VERSION 5.7 ;
  NOWIREEXTENSIONATPIN ON ;
  DIVIDERCHAR "/" ;
  BUSBITCHARS "[]" ;
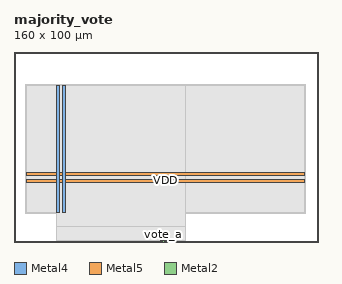
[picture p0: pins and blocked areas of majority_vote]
MACRO majority_vote
  CLASS BLOCK ;
  FOREIGN majority_vote ;
  ORIGIN 0.000 0.000 ;
  SIZE 160.000 BY 100.000 ;
  PIN VDD
    DIRECTION INOUT ;
    USE POWER ;
    PORT
      LAYER Metal4 ;
        RECT 22.240 15.380 23.840 82.620 ;
    END
    PORT
      LAYER Metal5 ;
        RECT 6.720 31.530 152.880 33.130 ;
    END
  END VDD
  PIN VSS
    DIRECTION INOUT ;
    USE GROUND ;
    PORT
      LAYER Metal4 ;
        RECT 25.540 15.380 27.140 82.620 ;
    END
    PORT
      LAYER Metal5 ;
        RECT 6.720 34.830 152.880 36.430 ;
    END
  END VSS
  PIN majority
    DIRECTION OUTPUT ;
    USE SIGNAL ;
    ANTENNADIFFAREA 0.897600 ;
    PORT
      LAYER Metal2 ;
        RECT 79.520 0.000 80.080 0.560 ;
    END
  END majority
  PIN vote_a
    DIRECTION INPUT ;
    USE SIGNAL ;
    ANTENNAGATEAREA 0.396000 ;
    PORT
      LAYER Metal2 ;
        RECT 78.400 0.000 78.960 0.560 ;
    END
  END vote_a
  PIN vote_b
    DIRECTION INPUT ;
    USE SIGNAL ;
    ANTENNAGATEAREA 0.396000 ;
    PORT
      LAYER Metal2 ;
        RECT 80.640 0.000 81.200 0.560 ;
    END
  END vote_b
  PIN vote_c
    DIRECTION INPUT ;
    USE SIGNAL ;
    ANTENNAGATEAREA 0.396000 ;
    PORT
      LAYER Metal2 ;
        RECT 77.280 0.000 77.840 0.560 ;
    END
  END vote_c
  OBS
      LAYER Nwell ;
        RECT 6.290 80.160 153.310 82.750 ;
      LAYER Pwell ;
        RECT 6.290 76.640 153.310 80.160 ;
      LAYER Nwell ;
        RECT 6.290 72.320 153.310 76.640 ;
      LAYER Pwell ;
        RECT 6.290 68.800 153.310 72.320 ;
      LAYER Nwell ;
        RECT 6.290 64.480 153.310 68.800 ;
      LAYER Pwell ;
        RECT 6.290 60.960 153.310 64.480 ;
      LAYER Nwell ;
        RECT 6.290 56.640 153.310 60.960 ;
      LAYER Pwell ;
        RECT 6.290 53.120 153.310 56.640 ;
      LAYER Nwell ;
        RECT 6.290 48.800 153.310 53.120 ;
      LAYER Pwell ;
        RECT 6.290 45.280 153.310 48.800 ;
      LAYER Nwell ;
        RECT 6.290 40.960 153.310 45.280 ;
      LAYER Pwell ;
        RECT 6.290 37.440 153.310 40.960 ;
      LAYER Nwell ;
        RECT 6.290 33.120 153.310 37.440 ;
      LAYER Pwell ;
        RECT 6.290 29.600 153.310 33.120 ;
      LAYER Nwell ;
        RECT 6.290 25.280 153.310 29.600 ;
      LAYER Pwell ;
        RECT 6.290 21.760 153.310 25.280 ;
      LAYER Nwell ;
        RECT 6.290 17.440 153.310 21.760 ;
      LAYER Pwell ;
        RECT 6.290 15.250 153.310 17.440 ;
      LAYER Metal1 ;
        RECT 6.720 15.380 152.880 82.620 ;
      LAYER Metal2 ;
        RECT 22.380 0.860 90.020 82.510 ;
        RECT 22.380 0.560 76.980 0.860 ;
        RECT 81.500 0.560 90.020 0.860 ;
      LAYER Metal3 ;
        RECT 22.330 7.980 90.070 82.460 ;
  END
END majority_vote
END LIBRARY

